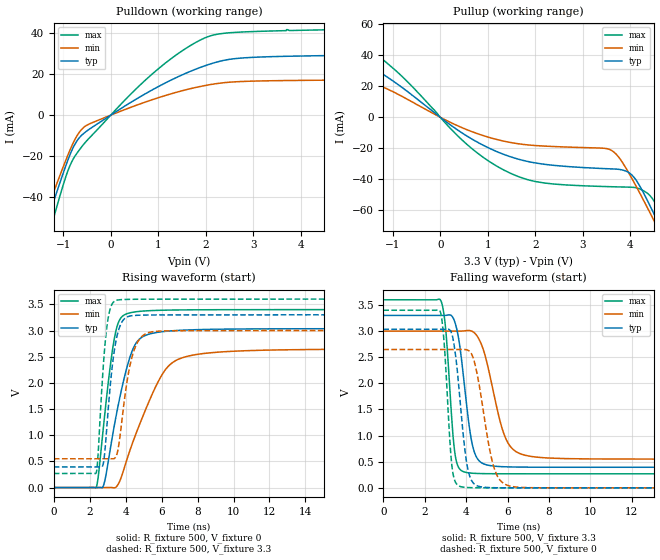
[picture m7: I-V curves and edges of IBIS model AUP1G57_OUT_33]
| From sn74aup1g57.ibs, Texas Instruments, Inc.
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[Model]   AUP1G57_OUT_33
Model_type  Output
Vref =   0
Rref =   1E6
Cref =   30p
Vmeas =   1.65
| variable   typ   min   max
C_comp   2.73pF   1.81pF   4.12pF
| C_pullup   3.12pF   1.81pF   4.12pF
| C_pulldown   2.33pF   2.13pF   2.90pF
[Temperature Range]   40   100   -40
| Ambient temperature   25   85   -40
[Voltage range]   3.3   3   3.6
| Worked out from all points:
|   slope of the pulldown table from 0 to 0.495 V, typ, clamps not added: 68.4 ohm
|   slope of the pullup table from 0 to 0.495 V, typ, clamps not added: 45.8 ohm
|   rising waveform, R_fixture 500, V_fixture 0: 20-80 % time 1.1ns typ, 1.9ns min, 686ps max; typ from 0 V to 3.04 V
|   falling waveform, R_fixture 500, V_fixture 3.3: 20-80 % time 536ps typ, 886ps min, 346ps max; typ from 3.3 V to 0.394 V
|   rising waveform, R_fixture 500, V_fixture 3.3: 20-80 % time 505ps typ, 659ps min, 392ps max; typ from 0.394 V to 3.3 V
|   falling waveform, R_fixture 500, V_fixture 0: 20-80 % time 457ps typ, 687ps min, 305ps max; typ from 3.04 V to 0 V
[Pulldown]
| AUP1G57_OUT_33
|   Voltage   I(typ)   I(min)   I(max)
-3.6V     -218.7mA   -196.3mA   -248.6mA
-1.515V   -64.37mA   -57.31mA   -75.82mA
-1.39V    -55.35mA   -49.29mA   -65.41mA
-1.275V   -47.14mA   -42mA      -55.89mA
-870mV    -19.93mA   -17.62mA   -25.18mA
-720mV    -12.85mA   -10.38mA   -18.82mA
-545mV    -8.444mA   -5.509mA   -13.51mA
940mV     13.13mA    8.018mA    21.36mA
1.5V      19.56mA    11.86mA    31.27mA
2.045V    24.53mA    14.67mA    38.2mA
3.1V      28.27mA    16.63mA    40.81mA
7.2V      29.73mA    17.36mA    42.67mA
[Pullup]
| AUP1G57_OUT_33
|   Voltage   I(typ)   I(min)   I(max)
-3.6V     42.88mA    27.27mA    57.92mA
-2.465V   31.53mA    19.52mA    45.85mA
-1.53V    32.87mA    22.09mA    44.95mA
-755mV    18.1mA     12.64mA    24.89mA
555mV     -11.98mA   -7.942mA   -17.3mA
1.65V     -27.07mA   -17.13mA   -38.31mA
3.61V     -33.32mA   -21.39mA   -44.82mA
4.08V     -38.63mA   -41.77mA   -45.28mA
4.375V    -54.25mA   -58.9mA    -49.24mA
4.565V    -66.24mA   -70.37mA   -57.33mA
4.775V    -80.02mA   -83.29mA   -71.37mA
7.2V      -250.7mA   -240.9mA   -257mA
[Ramp]
| AUP1G57_OUT_33
| variable   typ   min   max
dV/dt_r   1.82/1.10E-09   1.59/1.90E-09   2.04/6.89E-10
dV/dt_f   1.75/5.43E-10   1.48/8.92E-10   2.01/3.50E-10
R_load = 500
[Rising Waveform]
| AUP1G57_OUT_33
R_fixture =   500
C_fixture =   0
L_fixture =   0
V_fixture =   0
V_fixture_min = 0
V_fixture_max = 0
|   Time   V(typ)   V(min)   V(max)
0s        24.73nV    82.54nV    2.123nV
2.365ns   9.031uV    -3.183uV   10.16mV
2.795ns   73.28mV    -21.15uV   1.27V
3.365ns   1.181V     -5.19mV    2.841V
3.65ns    1.684V     109.3mV    3.196V
4.115ns   2.354V     585.9mV    3.327V
4.745ns   2.83V      1.183V     3.365V
6.02ns    2.977V     2.155V     3.388V
7.525ns   3.012V     2.516V     3.395V
30.7ns    3.035V     2.647V     3.399V
[Falling Waveform]
| AUP1G57_OUT_33
R_fixture =   500
C_fixture =   0
L_fixture =   0
V_fixture =   3.3
V_fixture_min = 3
V_fixture_max = 3.6
|   Time   V(typ)   V(min)   V(max)
0s        3.3V       3V         3.6V
2.785ns   3.3V       3V         3.58V
3.02ns    3.301V     3V         3.006V
3.455ns   3.173V     2.999V     672mV
3.915ns   1.977V     3.005V     303.5mV
4.245ns   936.7mV    3.004V     282.2mV
4.575ns   541.4mV    2.878V     274.9mV
5.875ns   403.4mV    980.6mV    269.7mV
6.89ns    396.4mV    620mV      269.4mV
30.7ns    394.1mV    550mV      269.3mV
[Rising Waveform]
| AUP1G57_OUT_33
R_fixture =   500
C_fixture =   0
L_fixture =   0
V_fixture =   3.3
V_fixture_min = 3
V_fixture_max = 3.6
|   Time   V(typ)   V(min)   V(max)
0s        394.1mV    550mV      269.3mV
2.36ns    394.1mV    550mV      283.6mV
2.46ns    394.4mV    550mV      619.4mV
2.74ns    437.3mV    550mV      2.256V
2.925ns   1.044V     550.2mV    2.994V
3.21ns    2.188V     550.7mV    3.485V
3.48ns    2.84V      608.4mV    3.577V
4.35ns    3.284V     2.493V     3.597V
5.335ns   3.296V     2.966V     3.599V
30.7ns    3.3V       3V         3.6V
[Falling Waveform]
| AUP1G57_OUT_33
R_fixture =   500
C_fixture =   0
L_fixture =   0
V_fixture =   0
V_fixture_min = 0
V_fixture_max = 0
|   Time   V(typ)   V(min)   V(max)
0s        3.035V     2.647V     3.399V
2.745ns   3.035V     2.647V     3.376V
2.94ns    3.035V     2.647V     2.765V
3.32ns    2.932V     2.647V     399.3mV
3.735ns   1.548V     2.648V     23.41mV
4.01ns    520.1mV    2.643V     8.05mV
4.285ns   125.2mV    2.543V     3.325mV
5.31ns    3.231mV    434.9mV    183.8uV
6.105ns   524.8uV    34.45mV    32.41uV
30.7ns    -25.97nV   46.1nV     -49.46nV
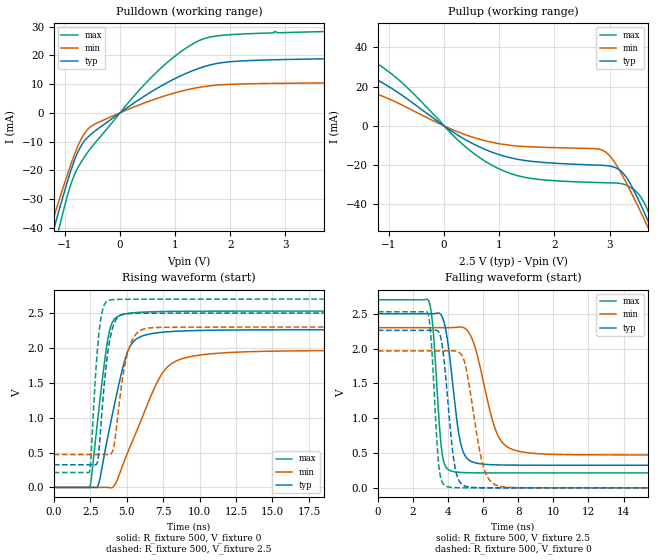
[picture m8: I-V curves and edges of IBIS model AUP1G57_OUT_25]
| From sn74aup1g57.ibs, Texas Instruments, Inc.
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[Model]   AUP1G57_OUT_25
Model_type  Output
Vref =   0
Rref =   1E6
Cref =   30p
Vmeas =   1.25
| variable   typ   min   max
C_comp   2.77pF   1.87pF   4.14pF
| C_pullup   3.12pF   1.87pF   4.14pF
| C_pulldown   2.42pF   2.13pF   2.99pF
[Temperature Range]   40   100   -40
| Ambient temperature   25   85   -40
[Voltage range]   2.5   2.3   2.7
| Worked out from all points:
|   slope of the pulldown table from 0 to 0.375 V, typ, clamps not added: 75.2 ohm
|   slope of the pullup table from 0 to 0.375 V, typ, clamps not added: 55.1 ohm
|   rising waveform, R_fixture 500, V_fixture 0: 20-80 % time 1.4ns typ, 2.39ns min, 856ps max; typ from 0 V to 2.26 V
|   falling waveform, R_fixture 500, V_fixture 2.5: 20-80 % time 625ps typ, 1.07ns min, 397ps max; typ from 2.5 V to 0.325 V
|   rising waveform, R_fixture 500, V_fixture 2.5: 20-80 % time 609ps typ, 785ps min, 469ps max; typ from 0.325 V to 2.5 V
|   falling waveform, R_fixture 500, V_fixture 0: 20-80 % time 516ps typ, 783ps min, 344ps max; typ from 2.26 V to 0 V
[Pulldown]
| AUP1G57_OUT_25
|   Voltage   I(typ)   I(min)   I(max)
-3.6V     -214mA     -193.5mA   -239.7mA
-1.26V    -44.55mA   -39.92mA   -52.42mA
-1.205V   -40.74mA   -36.52mA   -48.02mA
-1.115V   -34.57mA   -31.02mA   -40.91mA
-800mV    -15.22mA   -13.22mA   -20.4mA
-685mV    -10.84mA   -8.445mA   -16.54mA
-540mV    -7.689mA   -4.911mA   -12.5mA
675mV     8.558mA    5.038mA    14.35mA
1.105V    12.9mA     7.5mA      21.28mA
1.52V     16.03mA    9.129mA    25.76mA
2.585V    18.34mA    10.19mA    27.69mA
7.2V      19.61mA    10.73mA    29.61mA
[Pullup]
| AUP1G57_OUT_25
|   Voltage   I(typ)   I(min)   I(max)
-3.6V     37.28mA    23.5mA     50.35mA
-2.355V   24.65mA    15.21mA    35.57mA
-1.425V   26.01mA    17.2mA     35.58mA
-760mV    15.58mA    10.63mA    21.96mA
405mV     -7.279mA   -4.651mA   -11.04mA
1.05V     -15.07mA   -9.293mA   -22.54mA
2.845V    -20.04mA   -12.07mA   -28.88mA
3.17V     -22.17mA   -22.09mA   -29.2mA
3.455V    -33.67mA   -37.48mA   -32.73mA
3.685V    -47.61mA   -50.92mA   -42.5mA
3.82V     -56.28mA   -59.04mA   -51.47mA
7.2V      -294.7mA   -278.7mA   -311.5mA
[Ramp]
| AUP1G57_OUT_25
| variable   typ   min   max
dV/dt_r   1.36/1.40E-09   1.18/2.40E-09   1.52/8.57E-10
dV/dt_f   1.31/6.33E-10   1.10/1.07E-09   1.50/4.04E-10
R_load = 500
[Rising Waveform]
| AUP1G57_OUT_25
R_fixture =   500
C_fixture =   0
L_fixture =   0
V_fixture =   0
V_fixture_min = 0
V_fixture_max = 0
|   Time   V(typ)   V(min)   V(max)
0s        19.04nV    76.96nV    1.464nV
2.47ns    -20.67uV   4.864nV    10.08mV
3.06ns    41.27mV    -29.26uV   1.06V
3.71ns    734.4mV    -84.33uV   2.13V
4.57ns    1.578V     230.1mV    2.469V
5.09ns    1.96V      514mV      2.495V
5.645ns   2.125V     790mV      2.508V
7.395ns   2.224V     1.622V     2.522V
8.885ns   2.244V     1.851V     2.526V
32.79ns   2.261V     1.966V     2.528V
[Falling Waveform]
| AUP1G57_OUT_25
R_fixture =   500
C_fixture =   0
L_fixture =   0
V_fixture =   2.5
V_fixture_min = 2.3
V_fixture_max = 2.7
|   Time   V(typ)   V(min)   V(max)
0s        2.5V       2.3V       2.7V
2.895ns   2.5V       2.3V       2.685V
3.14ns    2.499V     2.3V       2.284V
3.64ns    2.468V     2.3V       529mV
4.2ns     1.638V     2.3V       239.6mV
4.62ns    763.2mV    2.308V     222.9mV
5.01ns    445.2mV    2.281V     217.9mV
6.76ns    330mV      796.9mV    214.5mV
7.915ns   326mV      532.1mV    214.4mV
32.79ns   324.7mV    472mV      214.4mV
[Rising Waveform]
| AUP1G57_OUT_25
R_fixture =   500
C_fixture =   0
L_fixture =   0
V_fixture =   2.5
V_fixture_min = 2.3
V_fixture_max = 2.7
|   Time   V(typ)   V(min)   V(max)
0s        324.7mV    472mV      214.4mV
2.45ns    324.7mV    472mV      226.3mV
2.945ns   335.5mV    472mV      1.855V
3.11ns    557mV      472mV      2.239V
3.385ns   1.302V     472.4mV    2.575V
3.765ns   2.026V     471.1mV    2.683V
4.13ns    2.347V     601.7mV    2.694V
5.085ns   2.492V     1.945V     2.698V
6.185ns   2.498V     2.272V     2.699V
32.79ns   2.5V       2.3V       2.7V
[Falling Waveform]
| AUP1G57_OUT_25
R_fixture =   500
C_fixture =   0
L_fixture =   0
V_fixture =   0
V_fixture_min = 0
V_fixture_max = 0
|   Time   V(typ)   V(min)   V(max)
0s        2.261V     1.966V     2.528V
2.84ns    2.26V      1.966V     2.51V
3.04ns    2.26V      1.966V     2.102V
3.475ns   2.235V     1.966V     312.1mV
3.93ns    1.406V     1.966V     18.64mV
4.295ns   452.5mV    1.968V     5.208mV
4.615ns   106.6mV    1.946V     1.913mV
6.01ns    1.336mV    305.2mV    51.73uV
6.89ns    234.8uV    26.09mV    9.731uV
32.79ns   -26.17nV   26.08nV    -38.26nV
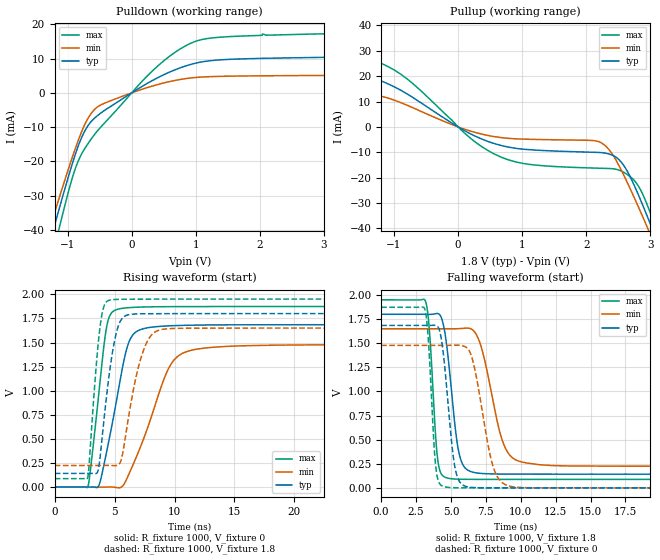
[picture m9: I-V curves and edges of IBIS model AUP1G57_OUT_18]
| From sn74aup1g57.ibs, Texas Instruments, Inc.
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[Model]   AUP1G57_OUT_18
Model_type  Output
Vref =   0
Rref =   1E6
Cref =   30p
Vmeas =   0.9
| variable   typ   min   max
C_comp   2.80pF   1.94pF   4.08pF
| C_pullup   3.08pF   1.94pF   4.08pF
| C_pulldown   2.52pF   2.14pF   3.04pF
[Temperature Range]   40   100   -40
| Ambient temperature   25   85   -40
[Voltage range]   1.8   1.65   1.95
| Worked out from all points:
|   slope of the pulldown table from 0 to 0.27 V, typ, clamps not added: 88.6 ohm
|   slope of the pullup table from 0 to 0.27 V, typ, clamps not added: 73.6 ohm
|   rising waveform, R_fixture 1000, V_fixture 0: 20-80 % time 1.56ns typ, 2.57ns min, 978ps max; typ from 0 V to 1.68 V
|   falling waveform, R_fixture 1000, V_fixture 1.8: 20-80 % time 738ps typ, 1.29ns min, 456ps max; typ from 1.8 V to 0.142 V
|   rising waveform, R_fixture 1000, V_fixture 1.8: 20-80 % time 996ps typ, 1.38ns min, 709ps max; typ from 0.142 V to 1.8 V
|   falling waveform, R_fixture 1000, V_fixture 0: 20-80 % time 667ps typ, 1.1ns min, 424ps max; typ from 1.68 V to 0 V
[Pulldown]
| AUP1G57_OUT_18
|   Voltage   I(typ)   I(min)   I(max)
-3.6V     -208.6mA   -189.9mA   -231.7mA
-1.27V    -43.16mA   -39.01mA   -50.14mA
-1.215V   -39.42mA   -35.66mA   -45.88mA
-1.125V   -33.38mA   -30.25mA   -38.97mA
-850mV    -16.31mA   -14.68mA   -20.63mA
-710mV    -10.41mA   -8.408mA   -15.6mA
-555mV    -6.973mA   -4.411mA   -11.55mA
360mV     3.96mA     2.185mA    7.039mA
705mV     6.927mA    3.722mA    12.18mA
1.03V     8.784mA    4.527mA    15.22mA
2.04V     10.05mA    4.966mA    17.1mA
7.2V      11.18mA    5.355mA    18.77mA
[Pullup]
| AUP1G57_OUT_18
|   Voltage   I(typ)   I(min)   I(max)
-3.6V     32.09mA    19.71mA    43.84mA
-3.16V    27.19mA    16.62mA    37.96mA
-2.12V    17.93mA    10.78mA    26.5mA
-1.525V   19.29mA    11.78mA    27.75mA
-1.155V   17.65mA    11.82mA    24.55mA
680mV     -7.373mA   -4.228mA   -12mA
2.185V    -10.05mA   -5.721mA   -16.26mA
2.485V    -12.35mA   -14.1mA    -16.81mA
2.725V    -21.81mA   -26.61mA   -20.47mA
2.94V     -34.55mA   -38.91mA   -30.08mA
3.085V    -43.74mA   -47.5mA    -39.77mA
7.2V      -334.8mA   -315.6mA   -357.6mA
[Ramp]
| AUP1G57_OUT_18
| variable   typ   min   max
dV/dt_r   1.01/1.56E-09   0.89/2.58E-09   1.13/9.82E-10
dV/dt_f   1.00/7.44E-10   0.86/1.30E-09   1.12/4.61E-10
R_load = 1000
[Rising Waveform]
| AUP1G57_OUT_18
R_fixture =   1000
C_fixture =   0
L_fixture =   0
V_fixture =   0
V_fixture_min = 0
V_fixture_max = 0
|   Time   V(typ)   V(min)   V(max)
0s        17.12nV    87.22nV    1.127nV
2.77ns    -22.46uV   16.24nV    7.166mV
3.65ns    9.061mV    -18.61uV   937.3mV
4.265ns   327.2mV    350uV      1.613V
5.08ns    845.8mV    -2.785mV   1.837V
5.935ns   1.399V     65.19mV    1.859V
6.56ns    1.585V     239.3mV    1.865V
9.405ns   1.672V     1.205V     1.872V
10.9ns    1.678V     1.401V     1.873V
35.9ns    1.685V     1.477V     1.873V
[Falling Waveform]
| AUP1G57_OUT_18
R_fixture =   1000
C_fixture =   0
L_fixture =   0
V_fixture =   1.8
V_fixture_min = 1.65
V_fixture_max = 1.95
|   Time   V(typ)   V(min)   V(max)
0s        1.8V       1.65V      1.95V
3.175ns   1.8V       1.65V      1.935V
3.46ns    1.799V     1.65V      1.623V
4.025ns   1.808V     1.65V      324mV
4.625ns   1.552V     1.649V     107.2mV
5.535ns   390.5mV    1.651V     89.97mV
6.475ns   166.4mV    1.646V     88.22mV
8.71ns    143.2mV    478.3mV    87.9mV
9.84ns    142.5mV    278mV      87.9mV
35.9ns    142.2mV    224.7mV    87.89mV
[Rising Waveform]
| AUP1G57_OUT_18
R_fixture =   1000
C_fixture =   0
L_fixture =   0
V_fixture =   1.8
V_fixture_min = 1.65
V_fixture_max = 1.95
|   Time   V(typ)   V(min)   V(max)
0s        142.2mV    224.7mV    87.89mV
2.75ns    142.2mV    224.7mV    99.37mV
3.74ns    264.5mV    224.7mV    1.618V
4.06ns    641mV      224.8mV    1.857V
4.49ns    1.113V     225.3mV    1.936V
5.05ns    1.551V     223.2mV    1.947V
5.6ns     1.746V     306.1mV    1.948V
7.13ns    1.798V     1.311V     1.95V
8.645ns   1.799V     1.626V     1.95V
35.9ns    1.8V       1.65V      1.95V
[Falling Waveform]
| AUP1G57_OUT_18
R_fixture =   1000
C_fixture =   0
L_fixture =   0
V_fixture =   0
V_fixture_min = 0
V_fixture_max = 0
|   Time   V(typ)   V(min)   V(max)
0s        1.685V     1.478V     1.873V
3.14ns    1.684V     1.478V     1.847V
3.385ns   1.684V     1.478V     1.522V
3.895ns   1.685V     1.477V     241mV
4.425ns   1.425V     1.477V     15.95mV
5.245ns   246.2mV    1.48V      1.334mV
6.04ns    16.13mV    1.462V     150.1uV
8ns       203.7uV    229.6mV    3.369uV
9.065ns   42.99uV    23.05mV    817.3nV
35.9ns    -25.85nV   32.2nV     -64.08nV
